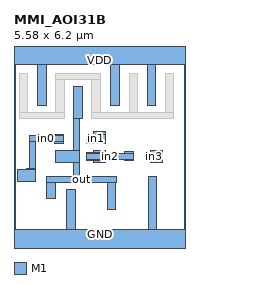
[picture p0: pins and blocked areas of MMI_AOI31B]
MACRO MMI_AOI31B
	CLASS CORE ;
	FOREIGN MMI_AOI31B 0 0 ;
	SIZE 5.58 BY 6.2 ;
	SYMMETRY X Y ;
	SITE CORE1 ;
	PIN out
		DIRECTION output ;
		USE SIGNAL ;
		PORT
			LAYER M1 ;
			RECT 1.945 4.03 2.225 5.09 ;
			LAYER M1 ;
			RECT 1.945 2.98 2.14 4.03 ;
			LAYER M1 ;
			RECT 1.36 2.6 2.14 2.98 ;
			LAYER M1 ;
			RECT 1.945 2.135 2.14 2.6 ;
			LAYER M1 ;
			RECT 1.175 2.13 3.335 2.135 ;
			LAYER M1 ;
			RECT 1.075 1.94 3.335 2.13 ;
			LAYER M1 ;
			RECT 1.075 1.43 1.355 1.94 ;
			LAYER M1 ;
			RECT 3.045 1.045 3.325 1.94 ;
		END
		AntennaDiffArea 1.48995 ;
	END out
	PIN in1
		DIRECTION input ;
		USE SIGNAL ;
		PORT
			LAYER M1 ;
			RECT 2.6 3.505 2.98 3.6 ;
			LAYER M1 ;
			RECT 2.35 3.225 2.98 3.505 ;
			LAYER M1 ;
			RECT 2.6 3.22 2.98 3.225 ;
		END
		AntennaGateArea 0.8085 ;
	END in1
	PIN GND
		DIRECTION inout ;
		USE GROUND ;
		PORT
			LAYER M1 ;
			RECT 1.715 0.42 1.995 1.715 ;
			LAYER M1 ;
			RECT 4.38 0.42 4.66 2.13 ;
			LAYER M1 ;
			RECT 0 -0.42 5.58 0.42 ;
		END
	END GND
	PIN in2
		DIRECTION input ;
		USE SIGNAL ;
		PORT
			LAYER M1 ;
			RECT 2.6 2.935 2.98 2.98 ;
			LAYER M1 ;
			RECT 2.35 2.885 2.98 2.935 ;
			LAYER M1 ;
			RECT 3.615 2.885 3.895 2.95 ;
			LAYER M1 ;
			RECT 2.35 2.695 3.895 2.885 ;
			LAYER M1 ;
			RECT 2.35 2.655 2.98 2.695 ;
			LAYER M1 ;
			RECT 3.615 2.67 3.895 2.695 ;
			LAYER M1 ;
			RECT 2.6 2.6 2.98 2.655 ;
		END
		AntennaGateArea 0.8085 ;
	END in2
	PIN VDD
		DIRECTION inout ;
		USE POWER ;
		PORT
			LAYER M1 ;
			RECT 0 5.78 5.58 6.62 ;
			LAYER M1 ;
			RECT 0.765 4.44 1.045 5.78 ;
			LAYER M1 ;
			RECT 3.165 4.44 3.445 5.78 ;
			LAYER M1 ;
			RECT 4.345 4.44 4.625 5.78 ;
		END
	END VDD
	PIN in3
		DIRECTION input ;
		USE SIGNAL ;
		PORT
			LAYER M1 ;
			RECT 4.46 2.93 4.84 2.98 ;
			LAYER M1 ;
			RECT 4.275 2.65 4.84 2.93 ;
			LAYER M1 ;
			RECT 4.46 2.6 4.84 2.65 ;
		END
		AntennaGateArea 0.8085 ;
	END in3
	PIN in0
		DIRECTION input ;
		USE SIGNAL ;
		PORT
			LAYER M1 ;
			RECT 1.335 3.465 1.615 3.505 ;
			LAYER M1 ;
			RECT 0.5 3.27 1.615 3.465 ;
			LAYER M1 ;
			RECT 0.5 2.405 0.69 3.27 ;
			LAYER M1 ;
			RECT 1.335 3.225 1.615 3.27 ;
			LAYER M1 ;
			RECT 0.41 2.36 0.69 2.405 ;
			LAYER M1 ;
			RECT 0.12 1.98 0.69 2.36 ;
		END
		AntennaGateArea 0.5775 ;
	END in0
	OBS
		LAYER M1 ;
		RECT 0.175 4.225 0.455 5.5 ;
		LAYER M1 ;
		RECT 1.355 5.315 2.815 5.505 ;
		LAYER M1 ;
		RECT 1.355 4.225 1.635 5.315 ;
		LAYER M1 ;
		RECT 0.175 4.03 1.635 4.225 ;
		LAYER M1 ;
		RECT 2.535 4.225 2.815 5.315 ;
		LAYER M1 ;
		RECT 3.755 4.225 4.035 5.5 ;
		LAYER M1 ;
		RECT 4.935 4.225 5.215 5.5 ;
		LAYER M1 ;
		RECT 2.535 4.03 5.215 4.225 ;
	END
END MMI_AOI31B
